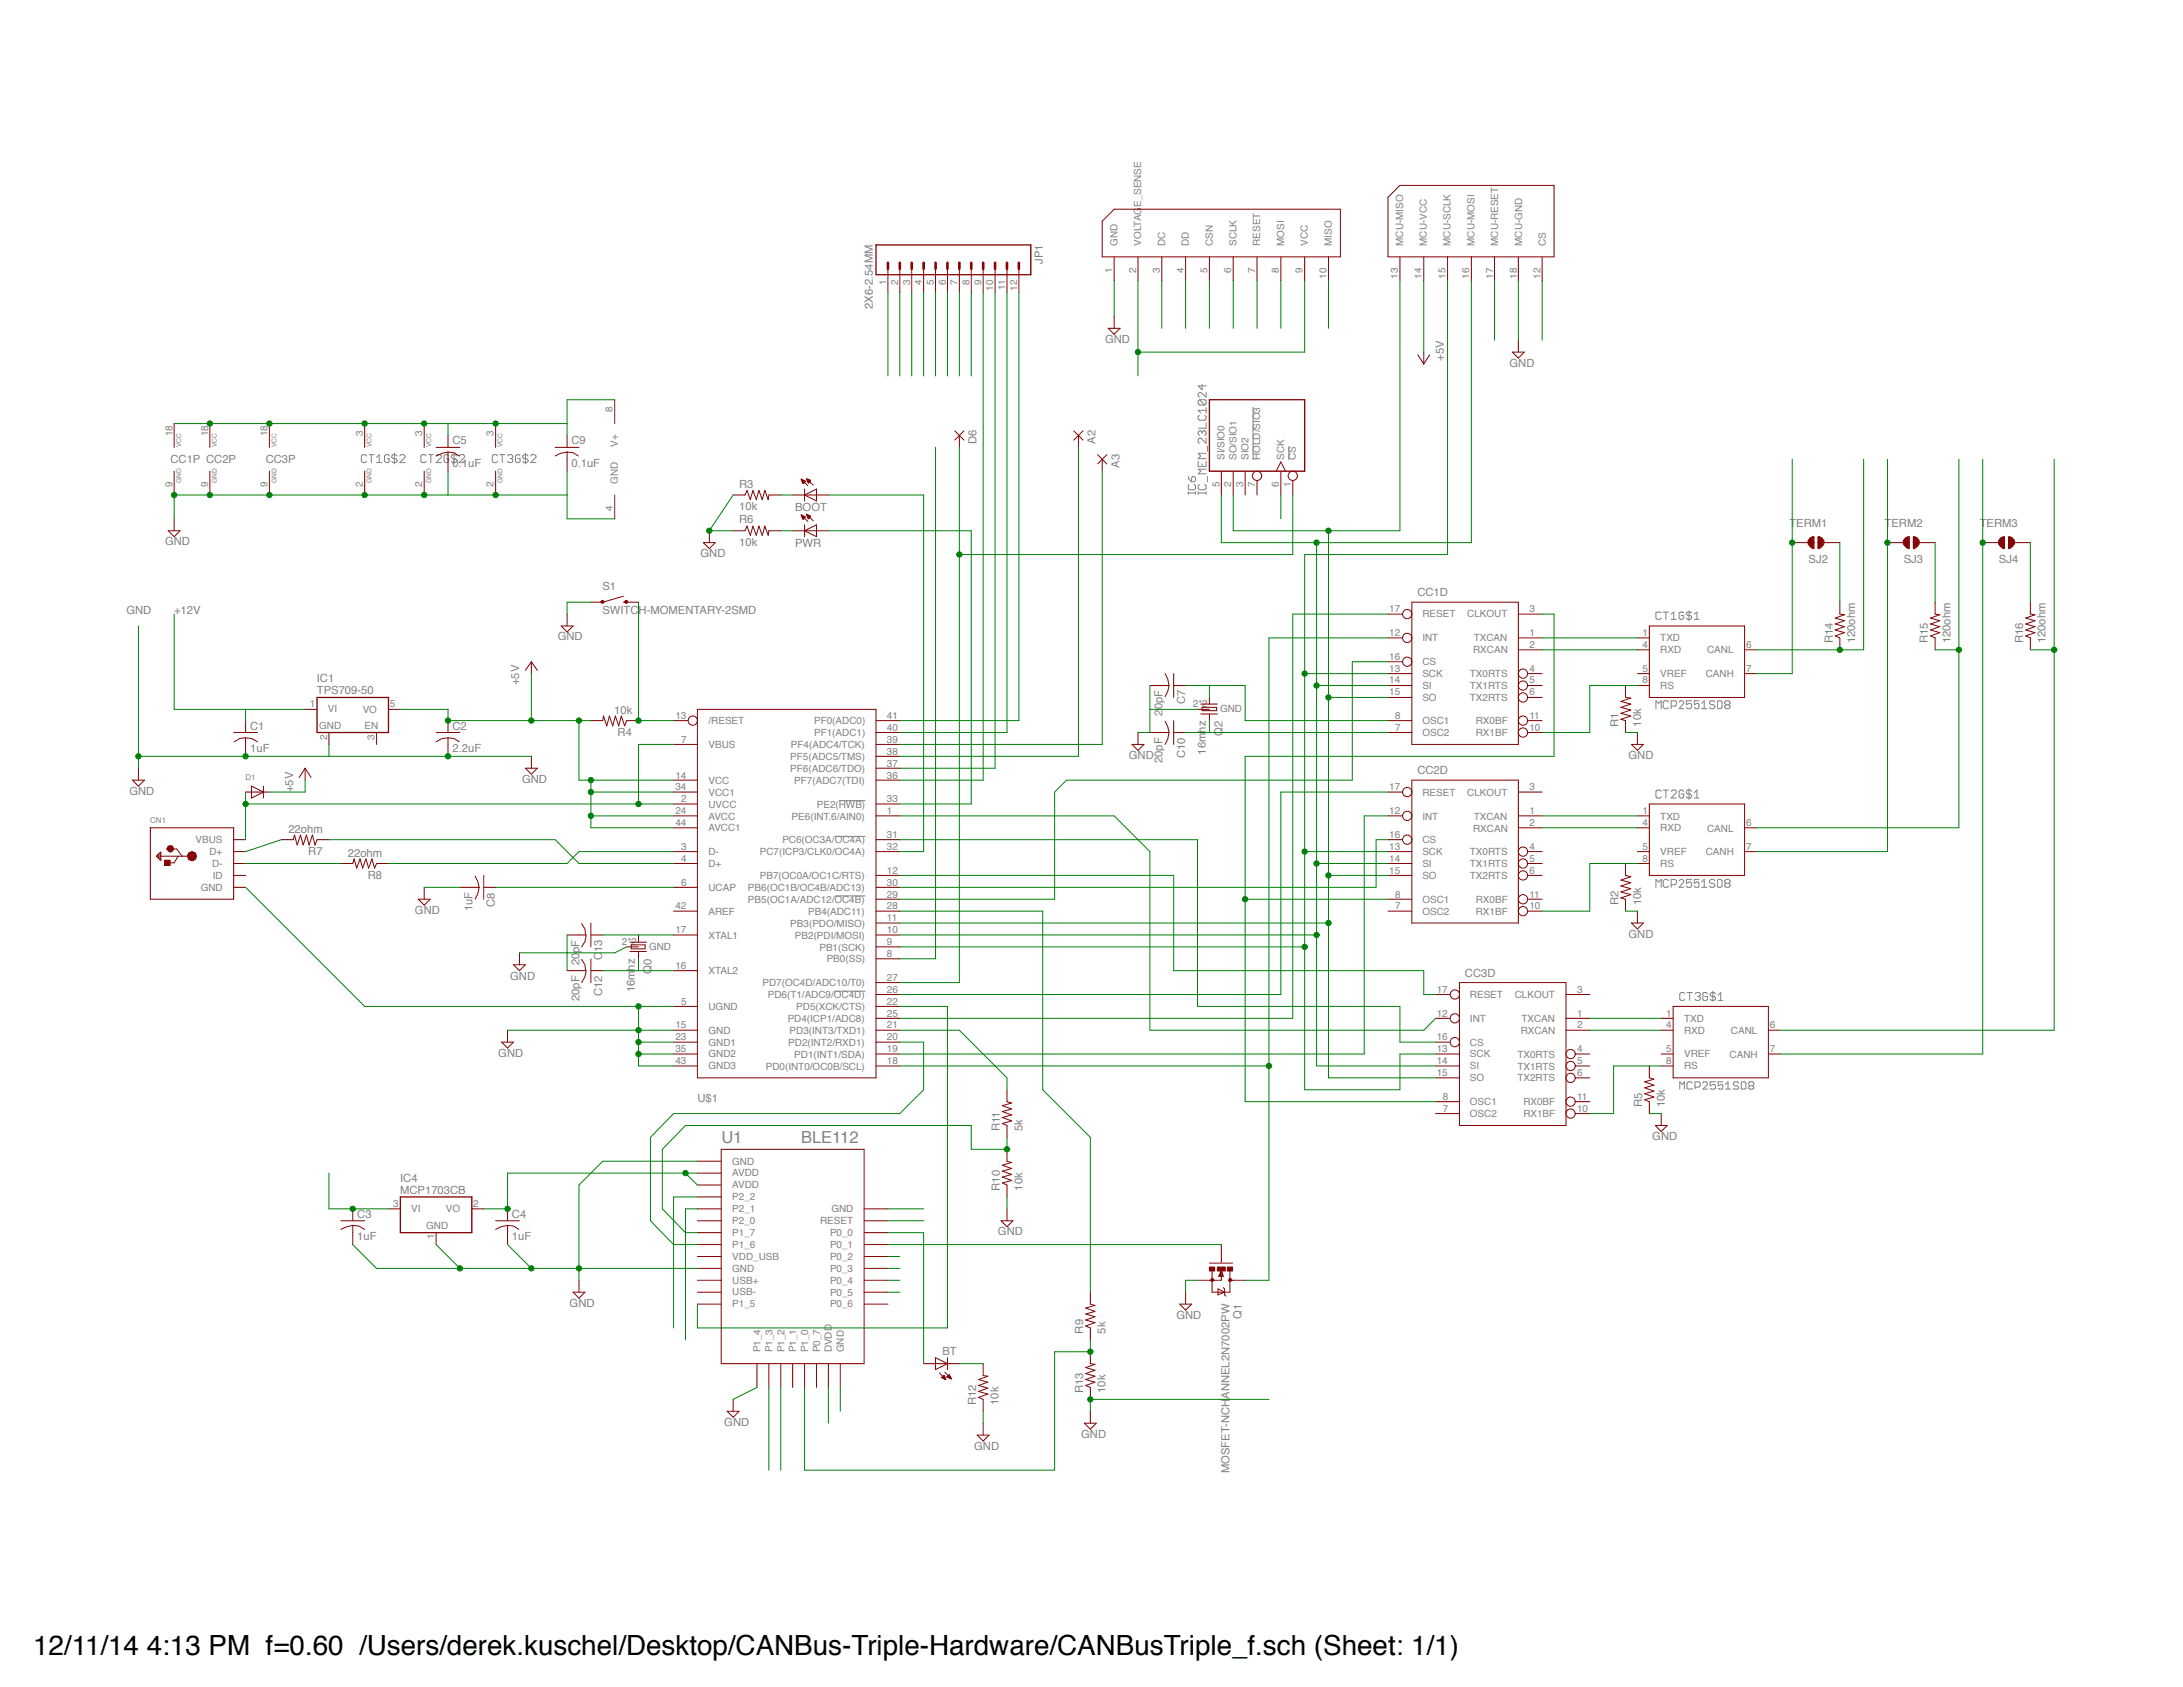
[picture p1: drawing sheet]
<svg xmlns="http://www.w3.org/2000/svg" width="279mm" height="216mm" viewBox="0 0 279 216" stroke-linecap="round" stroke-linejoin="round" font-family="sans-serif">
<defs><g id="words">
<text font-size="3.6" x="4.2" y="211.8">12/11/14 4:13 PM f=0.60 /Users/derek.kuschel/Desktop/CANBus-Triple-Hardware/CANBusTriple_f.sch (Sheet: 1/1)</text>
<g font-size="2.1" fill="#808080">
<text x="92.3" y="146.3">U1</text>
<text x="102.5" y="146.3">BLE112</text>
</g>
<g font-size="1.4" fill="#808080">
<text x="133.5" y="33.8" transform="rotate(-90 133.5 33.8)">JP1</text>
<text x="111.7" y="39.5" transform="rotate(-90 111.7 39.5)">2X6-2.54MM</text>
<text x="141.4" y="43.9">GND</text>
<text x="184.8" y="46.1" transform="rotate(-90 184.8 46.1)">+5V</text>
<text x="193.2" y="46.9">GND</text>
<text x="21.8" y="59.2">CC1P CC2P</text>
<text x="34" y="59.2">CC3P</text>
<text x="57.9" y="59.7">0.1uF</text>
<text x="57.9" y="56.8">C5</text>
<text x="73.1" y="59.7">0.1uF</text>
<text x="73.1" y="56.8">C9</text>
<text x="125" y="56.9" transform="rotate(-90 125 56.9)">D6</text>
<text x="140.2" y="56.8" transform="rotate(-90 140.2 56.8)">A2</text>
<text x="143.3" y="59.8" transform="rotate(-90 143.3 59.8)">A3</text>
<text x="94.6" y="65.3">10k</text>
<text x="94.6" y="62.4">R3</text>
<text x="101.8" y="65.4">BOOT</text>
<text x="21.1" y="69.8">GND</text>
<text x="89.7" y="71.3">GND</text>
<text x="94.6" y="69.9">10k</text>
<text x="94.6" y="67">R6</text>
<text x="101.8" y="70">PWR</text>
<text x="229" y="67.5">TERM1</text>
<text x="241.2" y="67.5">TERM2</text>
<text x="253.4" y="67.5">TERM3</text>
<text x="77.1" y="75.5">S1</text>
<text x="181.4" y="76.3">CC1D</text>
<text x="231.5" y="72">SJ2</text>
<text x="243.7" y="72">SJ3</text>
<text x="255.8" y="72">SJ4</text>
<text x="16.2" y="78.5">GND</text>
<text x="22.3" y="78.5">+12V</text>
<text x="71.4" y="82">GND</text>
<text x="77.1" y="78.5">SWITCH-MOMENTARY-2SMD</text>
<text x="234.6" y="82.3" transform="rotate(-90 234.6 82.3)">R14</text>
<text x="237.4" y="82.3" transform="rotate(-90 237.4 82.3)">120ohm</text>
<text x="246.7" y="82.3" transform="rotate(-90 246.7 82.3)">R15</text>
<text x="249.6" y="82.3" transform="rotate(-90 249.6 82.3)">120ohm</text>
<text x="258.9" y="82.3" transform="rotate(-90 258.9 82.3)">R16</text>
<text x="261.8" y="82.3" transform="rotate(-90 261.8 82.3)">120ohm</text>
<text x="40.6" y="88.8">TPS709-50</text>
<text x="40.6" y="87.3">IC1</text>
<text x="66.4" y="87.7" transform="rotate(-90 66.4 87.7)">+5V</text>
<text x="32" y="93.4">C1</text>
<text x="57.9" y="93.4">C2</text>
<text x="78.6" y="91.4">10k</text>
<text x="79" y="94.2">R4</text>
<text x="148.8" y="91.6" transform="rotate(-90 148.8 91.6)">20pF</text>
<text x="151.7" y="90.1" transform="rotate(-90 151.7 90.1)">C7</text>
<text x="156.5" y="94.2" transform="rotate(-90 156.5 94.2)">Q2</text>
<text x="207.2" y="93" transform="rotate(-90 207.2 93)">R1</text>
<text x="210" y="93" transform="rotate(-90 210 93)">10k</text>
<text x="16.6" y="101.8">GND</text>
<text x="32" y="96.3">1uF</text>
<text x="37.5" y="101.4" transform="rotate(-90 37.5 101.4)">+5V</text>
<text x="57.9" y="96.3">2.2uF</text>
<text x="66.8" y="100.2">GND</text>
<text x="144.5" y="97.2">GND</text>
<text x="148.8" y="97.7" transform="rotate(-90 148.8 97.7)">20pF</text>
<text x="151.7" y="97" transform="rotate(-90 151.7 97)">C10</text>
<text x="154.3" y="96.6" transform="rotate(-90 154.3 96.6)">16mhz</text>
<text x="181.4" y="99.1">CC2D</text>
<text x="208.4" y="97.2">GND</text>
<text x="36.9" y="106.6">22ohm</text>
<text x="39.4" y="109.5">R7</text>
<text x="44.5" y="109.6">22ohm</text>
<text x="47.1" y="112.5">R8</text>
<text x="53.1" y="117">GND</text>
<text x="60.5" y="116.6" transform="rotate(-90 60.5 116.6)">1uF</text>
<text x="63.4" y="116" transform="rotate(-90 63.4 116)">C8</text>
<text x="207.2" y="115.8" transform="rotate(-90 207.2 115.8)">R2</text>
<text x="210" y="115.8" transform="rotate(-90 210 115.8)">10k</text>
<text x="65.3" y="125.4">GND</text>
<text x="74.2" y="123.6" transform="rotate(-90 74.2 123.6)">20pF</text>
<text x="77.1" y="122.9" transform="rotate(-90 77.1 122.9)">C13</text>
<text x="83.4" y="124.6" transform="rotate(-90 83.4 124.6)">Q0</text>
<text x="187.5" y="125">CC3D</text>
<text x="208.4" y="120">GND</text>
<text x="74.2" y="128.1" transform="rotate(-90 74.2 128.1)">20pF</text>
<text x="77.1" y="127.5" transform="rotate(-90 77.1 127.5)">C12</text>
<text x="81.2" y="127" transform="rotate(-90 81.2 127)">16mhz</text>
<text x="63.8" y="135.3">GND</text>
<text x="89.3" y="141">U$1</text>
<text x="210.2" y="141.7" transform="rotate(-90 210.2 141.7)">R5</text>
<text x="213.1" y="141.7" transform="rotate(-90 213.1 141.7)">10k</text>
<text x="128" y="144.8" transform="rotate(-90 128 144.8)">R11</text>
<text x="130.8" y="144.8" transform="rotate(-90 130.8 144.8)">5k</text>
<text x="211.5" y="145.9">GND</text>
<text x="45.7" y="155.8">C3</text>
<text x="51.2" y="152.8">MCP1703CB</text>
<text x="51.2" y="151.2">IC4</text>
<text x="65.5" y="155.8">C4</text>
<text x="128" y="152.4" transform="rotate(-90 128 152.4)">R10</text>
<text x="130.8" y="152.4" transform="rotate(-90 130.8 152.4)">10k</text>
<text x="45.7" y="158.7">1uF</text>
<text x="65.5" y="158.7">1uF</text>
<text x="127.7" y="158.1">GND</text>
<text x="72.9" y="167.2">GND</text>
<text x="120.6" y="173.4">BT</text>
<text x="138.6" y="170.7" transform="rotate(-90 138.6 170.7)">R9</text>
<text x="141.5" y="170.7" transform="rotate(-90 141.5 170.7)">5k</text>
<text x="150.6" y="168.8">GND</text>
<text x="158.9" y="168.8" transform="rotate(-90 158.9 168.8)">Q1</text>
<text x="124.9" y="179.8" transform="rotate(-90 124.9 179.8)">R12</text>
<text x="127.8" y="179.8" transform="rotate(-90 127.8 179.8)">10k</text>
<text x="138.6" y="178.3" transform="rotate(-90 138.6 178.3)">R13</text>
<text x="141.5" y="178.3" transform="rotate(-90 141.5 178.3)">10k</text>
<text x="92.7" y="182.5">GND</text>
<text x="124.7" y="185.5">GND</text>
<text x="138.4" y="184">GND</text>
<text x="157.4" y="188.5" transform="rotate(-90 157.4 188.5)">MOSFET-NCHANNEL2N7002PW</text>
</g>
<g font-size="1.3" fill="#808080">
<text x="142.4" y="34.9" transform="rotate(-90 142.4 34.9)">1</text>
<text x="143" y="31.5" transform="rotate(-90 143 31.5)">GND</text>
<text x="145.4" y="34.9" transform="rotate(-90 145.4 34.9)">2</text>
<text x="146.1" y="31.5" transform="rotate(-90 146.1 31.5)">VOLTAGE_SENSE</text>
<text x="148.5" y="34.9" transform="rotate(-90 148.5 34.9)">3</text>
<text x="149.1" y="31.5" transform="rotate(-90 149.1 31.5)">DC</text>
<text x="151.5" y="34.9" transform="rotate(-90 151.5 34.9)">4</text>
<text x="152.2" y="31.5" transform="rotate(-90 152.2 31.5)">DD</text>
<text x="154.5" y="34.9" transform="rotate(-90 154.5 34.9)">5</text>
<text x="155.2" y="31.5" transform="rotate(-90 155.2 31.5)">CSN</text>
<text x="157.6" y="34.9" transform="rotate(-90 157.6 34.9)">6</text>
<text x="158.3" y="31.5" transform="rotate(-90 158.3 31.5)">SCLK</text>
<text x="160.6" y="34.9" transform="rotate(-90 160.6 34.9)">7</text>
<text x="161.3" y="31.5" transform="rotate(-90 161.3 31.5)">RESET</text>
<text x="163.7" y="34.9" transform="rotate(-90 163.7 34.9)">8</text>
<text x="164.3" y="31.5" transform="rotate(-90 164.3 31.5)">MOSI</text>
<text x="166.7" y="34.9" transform="rotate(-90 166.7 34.9)">9</text>
<text x="167.4" y="31.5" transform="rotate(-90 167.4 31.5)">VCC</text>
<text x="169.8" y="35.7" transform="rotate(-90 169.8 35.7)">10</text>
<text x="170.4" y="31.5" transform="rotate(-90 170.4 31.5)">MISO</text>
<text x="178.9" y="35.7" transform="rotate(-90 178.9 35.7)">13</text>
<text x="179.6" y="31.5" transform="rotate(-90 179.6 31.5)">MCU-MISO</text>
<text x="182" y="35.7" transform="rotate(-90 182 35.7)">14</text>
<text x="182.6" y="31.5" transform="rotate(-90 182.6 31.5)">MCU-VCC</text>
<text x="185" y="35.7" transform="rotate(-90 185 35.7)">15</text>
<text x="185.7" y="31.5" transform="rotate(-90 185.7 31.5)">MCU-SCLK</text>
<text x="188" y="35.7" transform="rotate(-90 188 35.7)">16</text>
<text x="188.7" y="31.5" transform="rotate(-90 188.7 31.5)">MCU-MOSI</text>
<text x="191.1" y="35.7" transform="rotate(-90 191.1 35.7)">17</text>
<text x="191.8" y="31.5" transform="rotate(-90 191.8 31.5)">MCU-RESET</text>
<text x="194.1" y="35.7" transform="rotate(-90 194.1 35.7)">18</text>
<text x="194.8" y="31.5" transform="rotate(-90 194.8 31.5)">MCU-GND</text>
<text x="197.2" y="35.7" transform="rotate(-90 197.2 35.7)">12</text>
<text x="197.9" y="31.5" transform="rotate(-90 197.9 31.5)">CS</text>
<text x="113.4" y="36.5" transform="rotate(-90 113.4 36.5)">1</text>
<text x="115" y="36.5" transform="rotate(-90 115 36.5)">2</text>
<text x="116.5" y="36.5" transform="rotate(-90 116.5 36.5)">3</text>
<text x="118" y="36.5" transform="rotate(-90 118 36.5)">4</text>
<text x="119.5" y="36.5" transform="rotate(-90 119.5 36.5)">5</text>
<text x="121" y="36.5" transform="rotate(-90 121 36.5)">6</text>
<text x="122.6" y="36.5" transform="rotate(-90 122.6 36.5)">7</text>
<text x="124.1" y="36.5" transform="rotate(-90 124.1 36.5)">8</text>
<text x="125.6" y="36.5" transform="rotate(-90 125.6 36.5)">9</text>
<text x="127.1" y="37.2" transform="rotate(-90 127.1 37.2)">10</text>
<text x="128.7" y="37.1" transform="rotate(-90 128.7 37.1)">11</text>
<text x="130.2" y="37.2" transform="rotate(-90 130.2 37.2)">12</text>
<text x="78.4" y="52.8" transform="rotate(-90 78.4 52.8)">8</text>
<text x="22.1" y="55.8" transform="rotate(-90 22.1 55.8)">18</text>
<text x="26.6" y="55.8" transform="rotate(-90 26.6 55.8)">18</text>
<text x="34.2" y="55.8" transform="rotate(-90 34.2 55.8)">18</text>
<text x="46.4" y="55.8" transform="rotate(-90 46.4 55.8)">3</text>
<text x="54" y="55.8" transform="rotate(-90 54 55.8)">3</text>
<text x="63.2" y="55.8" transform="rotate(-90 63.2 55.8)">3</text>
<text x="79.1" y="57.2" transform="rotate(-90 79.1 57.2)">V+</text>
<text x="156.7" y="58.9" transform="rotate(-90 156.7 58.9)">SI/SIO0</text>
<text x="158.3" y="58.9" transform="rotate(-90 158.3 58.9)">SO/SIO1</text>
<text x="159.8" y="58.9" transform="rotate(-90 159.8 58.9)">SIO2</text>
<text x="161.3" y="58.9" transform="rotate(-90 161.3 58.9)">HOLD/SIO3</text>
<text x="164.3" y="58.9" transform="rotate(-90 164.3 58.9)">SCK</text>
<text x="165.9" y="58.9" transform="rotate(-90 165.9 58.9)">CS</text>
<text x="22.1" y="62.3" transform="rotate(-90 22.1 62.3)">9</text>
<text x="26.6" y="62.3" transform="rotate(-90 26.6 62.3)">9</text>
<text x="34.2" y="62.3" transform="rotate(-90 34.2 62.3)">9</text>
<text x="46.4" y="62.3" transform="rotate(-90 46.4 62.3)">2</text>
<text x="54" y="62.3" transform="rotate(-90 54 62.3)">2</text>
<text x="63.2" y="62.3" transform="rotate(-90 63.2 62.3)">2</text>
<text x="78.4" y="65.4" transform="rotate(-90 78.4 65.4)">4</text>
<text x="79.1" y="61.9" transform="rotate(-90 79.1 61.9)">GND</text>
<text x="156.1" y="62.3" transform="rotate(-90 156.1 62.3)">5</text>
<text x="157.6" y="62.3" transform="rotate(-90 157.6 62.3)">2</text>
<text x="159.1" y="62.3" transform="rotate(-90 159.1 62.3)">3</text>
<text x="160.6" y="62.3" transform="rotate(-90 160.6 62.3)">7</text>
<text x="163.7" y="62.3" transform="rotate(-90 163.7 62.3)">6</text>
<text x="165.2" y="62.3" transform="rotate(-90 165.2 62.3)">1</text>
<text x="177.8" y="81.4">12</text>
<text x="177.8" y="78.3">17</text>
<text x="182" y="82">INT</text>
<text x="182" y="79">RESET</text>
<text x="187.8" y="79">CLKOUT</text>
<text x="188.5" y="83.6">RXCAN</text>
<text x="188.6" y="82.1">TXCAN</text>
<text x="195.7" y="78.3">3</text>
<text x="195.7" y="82.9">2</text>
<text x="195.7" y="81.4">1</text>
<text x="210.2" y="82.9">4</text>
<text x="210.2" y="81.4">1</text>
<text x="212.5" y="83.6">RXD</text>
<text x="212.5" y="82">TXD</text>
<text x="218.5" y="83.6">CANL</text>
<text x="223.5" y="82.9">6</text>
<text x="177.8" y="84.4">16</text>
<text x="177.8" y="85.9">13</text>
<text x="177.8" y="87.5">14</text>
<text x="177.8" y="89">15</text>
<text x="182" y="85.1">CS</text>
<text x="182" y="86.6">SCK</text>
<text x="182" y="88.1">SI</text>
<text x="182" y="89.7">SO</text>
<text x="188.1" y="86.6">TX0RTS</text>
<text x="188.1" y="88.1">TX1RTS</text>
<text x="188.1" y="89.7">TX2RTS</text>
<text x="195.7" y="85.9">4</text>
<text x="195.7" y="87.5">5</text>
<text x="195.7" y="89">6</text>
<text x="210.2" y="87.5">8</text>
<text x="210.2" y="85.9">5</text>
<text x="212.5" y="88.1">RS</text>
<text x="212.5" y="86.6">VREF</text>
<text x="218.3" y="86.6">CANH</text>
<text x="223.5" y="85.9">7</text>
<text x="39.7" y="90.5">1</text>
<text x="40.9" y="93.3">GND</text>
<text x="41.9" y="94.7" transform="rotate(-90 41.9 94.7)">2</text>
<text x="42" y="91.2">VI</text>
<text x="46.4" y="91.2">VO</text>
<text x="46.6" y="93.3">EN</text>
<text x="48" y="94.7" transform="rotate(-90 48 94.7)">3</text>
<text x="49.9" y="90.5">5</text>
<text x="86.4" y="92">13</text>
<text x="87.2" y="95.1">7</text>
<text x="90.7" y="92.7">/RESET</text>
<text x="90.7" y="95.7">VBUS</text>
<text x="101.2" y="95.8">PF4(ADC4/TCK)</text>
<text x="104.2" y="92.7">PF0(ADC0)</text>
<text x="104.2" y="94.2">PF1(ADC1)</text>
<text x="113.5" y="92">41</text>
<text x="113.5" y="93.6">40</text>
<text x="113.5" y="95.1">39</text>
<text x="152.7" y="90.5">2*2</text>
<text x="156.2" y="91.2">GND</text>
<text x="178.6" y="92">8</text>
<text x="178.6" y="93.6">7</text>
<text x="182" y="92.7">OSC1</text>
<text x="182" y="94.2">OSC2</text>
<text x="188.9" y="92.7">RX0BF</text>
<text x="188.9" y="94.2">RX1BF</text>
<text x="195.7" y="92">11</text>
<text x="195.7" y="93.6">10</text>
<text x="86.4" y="99.6">14</text>
<text x="86.4" y="101.2">34</text>
<text x="90.7" y="100.3">VCC</text>
<text x="90.7" y="101.8">VCC1</text>
<text x="101.2" y="97.3">PF5(ADC5/TMS)</text>
<text x="101.2" y="98.8">PF6(ADC6/TDO)</text>
<text x="101.7" y="100.3">PF7(ADC7(TDI)</text>
<text x="113.5" y="96.6">38</text>
<text x="113.5" y="98.1">37</text>
<text x="113.5" y="99.6">36</text>
<text x="177.8" y="101.2">17</text>
<text x="182" y="101.8">RESET</text>
<text x="187.8" y="101.9">CLKOUT</text>
<text x="195.7" y="101.2">3</text>
<text x="25" y="107.9">VBUS</text>
<text x="86.4" y="104.2">24</text>
<text x="86.4" y="105.7">44</text>
<text x="87.2" y="102.7">2</text>
<text x="90.7" y="103.4">UVCC</text>
<text x="90.7" y="104.9">AVCC</text>
<text x="90.7" y="106.4">AVCC1</text>
<text x="100.1" y="107.9">PC6(OC3A/OC4A)</text>
<text x="101.3" y="104.9">PE6(INT.6/AIN0)</text>
<text x="104.5" y="103.4">PE2(HWB)</text>
<text x="113.5" y="107.3">31</text>
<text x="113.5" y="102.7">33</text>
<text x="113.5" y="104.2">1</text>
<text x="177.8" y="107.3">16</text>
<text x="177.8" y="104.2">12</text>
<text x="182" y="107.9">CS</text>
<text x="182" y="104.9">INT</text>
<text x="188.5" y="106.4">RXCAN</text>
<text x="188.6" y="104.9">TXCAN</text>
<text x="195.7" y="105.7">2</text>
<text x="195.7" y="104.2">1</text>
<text x="210.2" y="105.7">4</text>
<text x="210.2" y="104.2">1</text>
<text x="212.5" y="106.4">RXD</text>
<text x="212.5" y="104.9">TXD</text>
<text x="218.5" y="106.4">CANL</text>
<text x="223.5" y="105.7">6</text>
<text x="26.8" y="109.5">D+</text>
<text x="27.1" y="111">D-</text>
<text x="27.2" y="112.5">ID</text>
<text x="87.2" y="108.8">3</text>
<text x="87.2" y="110.3">4</text>
<text x="87.2" y="113.3">6</text>
<text x="90.7" y="109.4">D-</text>
<text x="90.7" y="111">D+</text>
<text x="97.3" y="109.5">PC7(ICP3/CLK0/OC4A)</text>
<text x="97.3" y="112.5">PB7(OC0A/OC1C/RTS)</text>
<text x="113.5" y="108.8">32</text>
<text x="113.5" y="113.3">30</text>
<text x="113.5" y="111.8">12</text>
<text x="177.8" y="108.8">13</text>
<text x="177.8" y="110.3">14</text>
<text x="177.8" y="111.8">15</text>
<text x="182" y="109.4">SCK</text>
<text x="182" y="111">SI</text>
<text x="182" y="112.5">SO</text>
<text x="188.1" y="109.5">TX0RTS</text>
<text x="188.1" y="111">TX1RTS</text>
<text x="188.1" y="112.5">TX2RTS</text>
<text x="195.7" y="108.8">4</text>
<text x="195.7" y="110.3">5</text>
<text x="195.7" y="111.8">6</text>
<text x="210.2" y="110.3">8</text>
<text x="210.2" y="108.8">5</text>
<text x="212.5" y="111">RS</text>
<text x="212.5" y="109.4">VREF</text>
<text x="218.3" y="109.5">CANH</text>
<text x="223.5" y="108.8">7</text>
<text x="25.7" y="114">GND</text>
<text x="86.4" y="119.4">17</text>
<text x="86.4" y="116.4">42</text>
<text x="90.7" y="114">UCAP</text>
<text x="90.7" y="117.1">AREF</text>
<text x="95.7" y="114">PB6(OC1B/OC4B/ADC13)</text>
<text x="95.7" y="115.6">PB5(OC1A/ADC12/OC4B)</text>
<text x="101.2" y="118.6">PB3(PDO/MISO)</text>
<text x="103.4" y="117.1">PB4(ADC11)</text>
<text x="113.5" y="117.9">11</text>
<text x="113.5" y="119.4">10</text>
<text x="113.5" y="116.4">28</text>
<text x="113.5" y="114.9">29</text>
<text x="178.6" y="114.9">8</text>
<text x="178.6" y="116.4">7</text>
<text x="182" y="115.5">OSC1</text>
<text x="182" y="117.1">OSC2</text>
<text x="188.9" y="115.6">RX0BF</text>
<text x="188.9" y="117.1">RX1BF</text>
<text x="195.7" y="114.9">11</text>
<text x="195.7" y="116.4">10</text>
<text x="79.6" y="121">2*2</text>
<text x="83.1" y="121.6">GND</text>
<text x="86.4" y="124">16</text>
<text x="90.7" y="124.7">XTAL2</text>
<text x="90.7" y="120.1">XTAL1</text>
<text x="101.7" y="120.1">PB2(PDI/MOSI)</text>
<text x="104.9" y="121.6">PB1(SCK)</text>
<text x="105.8" y="123.2">PB0(SS)</text>
<text x="113.5" y="121">9</text>
<text x="113.5" y="122.5">8</text>
<text x="113.5" y="125.5">27</text>
<text x="86.4" y="131.6">15</text>
<text x="87.2" y="128.6">5</text>
<text x="90.7" y="129.2">UGND</text>
<text x="97.6" y="126.2">PD7(OC4D/ADC10/T0)</text>
<text x="98.3" y="127.7">PD6(T1/ADC9/OC4D)</text>
<text x="100.8" y="130.8">PD4(ICP1/ADC8)</text>
<text x="101.9" y="129.3">PD5(XCK/CTS)</text>
<text x="113.5" y="127.1">26</text>
<text x="113.5" y="128.6">22</text>
<text x="113.5" y="130.1">25</text>
<text x="113.5" y="131.6">21</text>
<text x="183.9" y="130.1">12</text>
<text x="183.9" y="127.1">17</text>
<text x="188.1" y="130.8">INT</text>
<text x="188.1" y="127.7">RESET</text>
<text x="193.9" y="127.7">CLKOUT</text>
<text x="194.7" y="130.8">TXCAN</text>
<text x="201.8" y="127.1">3</text>
<text x="201.8" y="131.6">2</text>
<text x="201.8" y="130.1">1</text>
<text x="213.3" y="131.6">4</text>
<text x="213.3" y="130.1">1</text>
<text x="215.5" y="130.8">TXD</text>
<text x="226.5" y="131.6">6</text>
<text x="86.4" y="133.1">23</text>
<text x="86.4" y="134.7">35</text>
<text x="86.4" y="136.2">43</text>
<text x="90.7" y="132.3">GND</text>
<text x="90.7" y="133.8">GND1</text>
<text x="90.7" y="135.3">GND2</text>
<text x="90.7" y="136.9">GND3</text>
<text x="98" y="136.9">PD0(INT0/OC0B/SCL)</text>
<text x="100.9" y="133.8">PD2(INT2/RXD1)</text>
<text x="101.1" y="132.3">PD3(INT3/TXD1)</text>
<text x="101.7" y="135.4">PD1(INT1/SDA)</text>
<text x="113.5" y="133.1">20</text>
<text x="113.5" y="134.7">19</text>
<text x="113.5" y="136.2">18</text>
<text x="183.9" y="133.1">16</text>
<text x="183.9" y="134.7">13</text>
<text x="183.9" y="136.2">14</text>
<text x="183.9" y="137.7">15</text>
<text x="188.1" y="133.8">CS</text>
<text x="188.1" y="135.3">SCK</text>
<text x="188.1" y="136.9">SI</text>
<text x="194.2" y="135.4">TX0RTS</text>
<text x="194.2" y="136.9">TX1RTS</text>
<text x="194.6" y="132.3">RXCAN</text>
<text x="201.8" y="134.7">4</text>
<text x="201.8" y="136.2">5</text>
<text x="201.8" y="137.7">6</text>
<text x="213.3" y="136.2">8</text>
<text x="213.3" y="134.7">5</text>
<text x="215.5" y="136.9">RS</text>
<text x="215.5" y="132.3">RXD</text>
<text x="215.5" y="135.3">VREF</text>
<text x="221.4" y="135.4">CANH</text>
<text x="221.5" y="132.3">CANL</text>
<text x="226.5" y="134.7">7</text>
<text x="184.7" y="140.8">8</text>
<text x="184.7" y="142.3">7</text>
<text x="188.1" y="141.4">OSC1</text>
<text x="188.1" y="142.9">OSC2</text>
<text x="188.1" y="138.4">SO</text>
<text x="194.2" y="138.4">TX2RTS</text>
<text x="195" y="141.4">RX0BF</text>
<text x="195" y="143">RX1BF</text>
<text x="201.8" y="140.8">11</text>
<text x="201.8" y="142.3">10</text>
<text x="93.7" y="149">GND</text>
<text x="50.3" y="154.5">3</text>
<text x="52.6" y="155.1">VI</text>
<text x="57.1" y="155.1">VO</text>
<text x="60.6" y="154.5">2</text>
<text x="93.7" y="150.6">AVDD</text>
<text x="93.7" y="152.1">AVDD</text>
<text x="93.7" y="155.1">P2_1</text>
<text x="93.7" y="153.6">P2_2</text>
<text x="106.4" y="155.1">GND</text>
<text x="54.6" y="157.3">GND</text>
<text x="55.6" y="158.6" transform="rotate(-90 55.6 158.6)">1</text>
<text x="93.7" y="159.7">P1_6</text>
<text x="93.7" y="158.2">P1_7</text>
<text x="93.7" y="156.7">P2_0</text>
<text x="93.7" y="161.2">VDD_USB</text>
<text x="105" y="156.7">RESET</text>
<text x="106.2" y="158.2">P0_0</text>
<text x="106.2" y="159.7">P0_1</text>
<text x="106.2" y="161.2">P0_2</text>
<text x="93.7" y="162.7">GND</text>
<text x="93.7" y="167.3">P1_5</text>
<text x="93.7" y="164.3">USB+</text>
<text x="93.7" y="165.8">USB-</text>
<text x="106.2" y="162.8">P0_3</text>
<text x="106.2" y="164.3">P0_4</text>
<text x="106.2" y="165.8">P0_5</text>
<text x="106.2" y="167.3">P0_6</text>
<text x="97.3" y="173.1" transform="rotate(-90 97.3 173.1)">P1_4</text>
<text x="98.9" y="173.1" transform="rotate(-90 98.9 173.1)">P1_3</text>
<text x="100.4" y="173.1" transform="rotate(-90 100.4 173.1)">P1_2</text>
<text x="101.9" y="173.1" transform="rotate(-90 101.9 173.1)">P1_1</text>
<text x="103.4" y="173.1" transform="rotate(-90 103.4 173.1)">P1_0</text>
<text x="105" y="173.1" transform="rotate(-90 105 173.1)">P0_7</text>
<text x="106.5" y="173.1" transform="rotate(-90 106.5 173.1)">DVDD</text>
<text x="108" y="173.1" transform="rotate(-90 108 173.1)">GND</text>
</g>
<g font-size="1" fill="#808080">
<text x="31.4" y="99.9">D1</text>
<text x="19.2" y="105.3">CN1</text>
</g>
<g font-size=".8" fill="#808080">
<text x="23.2" y="57.2" transform="rotate(-90 23.2 57.2)">VCC</text>
<text x="27.8" y="57.2" transform="rotate(-90 27.8 57.2)">VCC</text>
<text x="35.4" y="57.2" transform="rotate(-90 35.4 57.2)">VCC</text>
<text x="47.6" y="57.2" transform="rotate(-90 47.6 57.2)">VCC</text>
<text x="55.2" y="57.2" transform="rotate(-90 55.2 57.2)">VCC</text>
<text x="64.3" y="57.2" transform="rotate(-90 64.3 57.2)">VCC</text>
<text x="23.2" y="61.8" transform="rotate(-90 23.2 61.8)">GND</text>
<text x="27.8" y="61.8" transform="rotate(-90 27.8 61.8)">GND</text>
<text x="35.4" y="61.8" transform="rotate(-90 35.4 61.8)">GND</text>
<text x="47.6" y="61.8" transform="rotate(-90 47.6 61.8)">GND</text>
<text x="55.2" y="61.8" transform="rotate(-90 55.2 61.8)">GND</text>
<text x="64.3" y="61.8" transform="rotate(-90 64.3 61.8)">GND</text>
</g>
</g></defs>
<g fill="none" stroke="#808080" stroke-width=".13">
<path d="M46.9 58.4l-.1-.2h-.4l-.2 .2v.6l.2 .2h.4l.1-.2M47.3 58.2h.6M47.5 58.2v1M48.2 59.2h.7M48.2 58.5l.3-.3v1M49.8 58.4l-.1-.2h-.3l-.2 .2v.6l.2 .2h.3l.1-.2v-.3h-.2M50.5 58v1.4M50.8 58.4l-.1-.2h-.4l-.2 .2v.1l.2 .2h.4l.1 .2v.1l-.1 .2h-.4l-.2-.2M51.2 58.4l.1-.2h.4l.1 .2v.1l-.6 .7h.6M54.5 58.4l-.1-.2h-.4l-.1 .2v.6l.1 .2h.4l.1-.2M54.9 58.2h.6M55.1 58.2v1"/>
<path d="M55.8 58.4l.2-.2h.3l.2 .2v.1l-.7 .7h.7M57.4 58.4l-.1-.2h-.3l-.2 .2v.6l.2 .2h.3l.1-.2v-.3h-.2M58.1 58v1.4M58.4 58.4l-.1-.2h-.4l-.1 .2v.1l.1 .2h.4l.1 .2v.1l-.1 .2h-.4l-.1-.2M58.8 58.4l.1-.2h.4l.2 .2v.1l-.7 .7h.7M63.7 58.4l-.2-.2h-.3l-.2 .2v.6l.2 .2h.3l.2-.2M63.9 58.2h.7M64.3 58.2v1M65 58.4l.1-.2h.4l.1 .2v.1l-.1 .2M65.3 58.7h.2M65.5 58.7l.1 .2v.1l-.1 .2h-.4l-.1-.2M66.6 58.4l-.2-.2h-.3l-.1 .2v.6l.1 .2h.3l.2-.2v-.3h-.4"/>
<path d="M67.2 58v1.4M67.6 58.4l-.2-.2h-.3l-.2 .2v.1l.2 .2h.3l.2 .2v.1l-.2 .2h-.3l-.2-.2M67.9 58.4l.2-.2h.3l.2 .2v.1l-.7 .7h.7M153.4 59v.7h1v-.7M153.5 51.2h.7l.2 .1v.4l-.2 .1M153.5 53.2l-.1 .1v.3l.1 .2h.7l.2-.2v-.3l-.2-.1M153.5 51.2l-.1 .1v.4l.1 .1h.7M153.5 51.2l.7 .6M153.9 55.3l.1-.2h.2l.2 .2v.3l-.2 .1M153.9 55.3l-.2-.2h-.2l-.1 .2v.3l.1 .1M153.9 49.2v.7l-.5-.5h1M153.9 55.3v.2"/>
<path d="M153.9 59.4v.3M154.4 50.2v.6l-.7-.6h-.2l-.1 .2v.3l.1 .1M154.4 52.2v.7M154.4 54.1v.7h-1M154.4 56.1v.6l-.7-.6h-.2l-.1 .1v.4l.1 .1M154.4 58h-1l.3 .4-.3 .3h1M154.4 52.5h-1l.3 .4M154.5 57.1v.7M160.4 52.1v6.8M165 57.1v1.8M152.1 63.1h.9M152.1 61l.1 .3 .3 .4"/>
<path d="M152.1 62.9v.4M152.2 62l-.1 .2 .1 .5h.6l.2-.2v-.3l-.2-.2M152.5 61.2l.2-.2h.1l.2 .2v.3l-.2 .2h-.3zM153 62.9v.4M153.4 63.1h1M153.4 62.9v.4M153.5 62l-.1 .2v.3l.1 .2h.7l.2-.2v-.3l-.2-.2M154.4 62.9v.4M154.4 60h-1l.3 .3-.3 .3h1M154.5 61v.7M212.6 78.4l-.2-.1-.5 .1v.7l.2 .2h.3l.2-.2M212.9 78.3h.7"/>
<path d="M213.2 78.3v1M213.9 79.3h.7M213.9 78.6l.3-.3v1M215.5 78.4l-.2-.1-.4 .1v.7l.2 .2h.2l.2-.2v-.3h-.3M216.2 78.2v1.2M216.5 78.4l-.2-.1-.5 .1v.2l.2 .2h.3l.2 .1v.2l-.2 .2h-.3l-.2-.2M216.9 79.3h.5M216.9 78.6l.3-.3v1M211.9 90.7v-1l.4 .3 .3-.3v1M213.6 89.9l-.2-.2h-.4l-.1 .2v.6l.1 .2h.4l.2-.2M213.9 90.4h.5l.2-.2v-.3l-.2-.2h-.5v1M214.9 89.9l.2-.2h.2l.2 .2v.1l-.6 .7h.6"/>
<path d="M216.5 89.7h-.7v.5l.4-.2h.1l.2 .2v.3l-.2 .2h-.3l-.2-.2M217.4 89.7h-.5v.5l.5-.2v.2v.5h-.4l-.1-.2M217.8 90.7h.7M217.8 90l.3-.3v1M219.5 89.9l-.2-.2h-.3l-.2 .2v.1l.2 .2h.3l.2 .2v.1l-.2 .2h-.3l-.2-.2M219.9 89.7h.3l.2 .2v.6l-.2 .2h-.3l-.1-.2v-.6zM220.9 90.2l-.2-.2v-.1l.2-.2h.4l.1 .2v.1l-.1 .2M220.9 90.2l-.2 .2v.1l.2 .2h.4l.1-.2v-.1l-.1-.2M220.9 90.2h.4M106.9 107h3.9M106.9 114.7h3.9M107.4 102.5h3.4"/>
<path d="M211.9 113.6v-1.1l.4 .4 .3-.4v1.1M212.6 101.3l-.2-.2h-.3l-.2 .2v.7l.2 .1h.3l.2-.1M212.9 101.1h.7M213.2 101.1v1M213.6 112.7l-.2-.2h-.4l-.1 .2v.7l.1 .2h.4l.2-.2M213.9 113.2h.5l.2-.1v-.4l-.2-.2h-.5v1.1M213.9 101.3l.2-.2h.3l.2 .2v.2l-.7 .6h.7M214.9 112.7l.2-.2h.2l.2 .2v.2l-.6 .7h.6M215.5 101.3l-.2-.2h-.2l-.2 .2v.7l.2 .1h.2l.2-.1v-.4h-.3M216.2 100.9v1.4M216.5 101.3l-.2-.2h-.3l-.2 .2v.2l.2 .1h.3l.2 .2v.2l-.2 .1h-.3l-.2-.1M216.5 112.5h-.7v.6l.4-.2h.1l.2 .2v.3l-.2 .2h-.3l-.2-.2"/>
<path d="M216.9 101.5l.3-.4v1M216.9 102.1h.5M217.4 112.5h-.5v.6l.5-.2v.2v.5h-.4l-.1-.2M217.8 112.9l.3-.4v1.1M217.8 113.6h.7M219.5 112.7l-.2-.2h-.3l-.2 .2v.2l.2 .2h.3l.2 .1v.2l-.2 .2h-.3l-.2-.2M219.9 112.5h.3l.2 .2v.7l-.2 .2h-.3l-.1-.2v-.7zM220.9 113.1l-.2-.2v-.2l.2-.2h.4l.1 .2v.2l-.1 .2M220.9 113.1l-.2 .1v.2l.2 .2h.4l.1-.2v-.2l-.1-.1M220.9 113.1h.4M106.8 126.9h4M215 139.4v-.9l.3 .3 .3-.3v.9"/>
<path d="M215.6 127.2l-.1-.2h-.3l-.2 .2v.7l.2 .1h.3l.1-.1M215.9 127h.7M216.3 127v1M216.6 138.6l-.2-.1h-.3l-.2 .1v.7l.2 .1 .5-.1M216.9 127.2l.2-.2h.3l.2 .2v.2l-.2 .1M216.9 139.1h.5l.2-.1v-.4l-.2-.1h-.5v.9M217.3 127.5h.1M217.4 127.5l.2 .2v.2l-.2 .1h-.3l-.2-.1M218 138.6v-.1h.4l.1 .1v.2l-.5 .6h.5M218.5 127.2l-.1-.2h-.4v.2v.7v.1h.4l.1-.1v-.4h-.3M219.2 126.9v1.2M219.6 127.2l-.2-.2h-.3l-.2 .2v.2l.2 .1h.3l.2 .2v.2l-.2 .1h-.3l-.2-.1"/>
<path d="M219.6 138.5h-.7v.5l.3-.2h.2l.2 .2v.3l-.2 .1-.5-.1M219.9 128h.6M219.9 127.4l.3-.4v1M220.5 138.5h-.6v.5l.3-.2h.2l.1 .2v.3l-.1 .1-.5-.1M220.8 139.4h.7M220.8 138.8l.4-.3v.9M222.5 138.6l-.1-.1h-.4l-.2 .1v.2l.2 .2h.4l.1 .1v.2l-.1 .1-.6-.1M222.9 138.5h.4l.2 .1v.7l-.2 .1h-.4v-.1v-.7zM224 139l-.2-.2v-.2l.2-.1h.3l.2 .1v.2l-.2 .2M224 139l-.2 .1v.2l.2 .1 .5-.1v-.2l-.2-.1M224 139h.3"/>
</g>
<g fill="none" stroke="#830203" stroke-width=".13">
<path d="M22.3 54.2v3.1M26.9 54.2v3.1M46.7 54.2v3.1M54.3 54.2v3.1M22.3 60.3v3.1M26.9 60.3v3.1M46.7 60.3v3.1M54.3 60.3v3.1M177.7 78.6h1.8M180.7 77.1h13.6v18.2h-13.6zM194.3 78.6h3.1M29.9 93.7h3.1"/>
<path d="M31.4 94.4l.8 .1 .8 .4M31.4 94.4l-.7 .1-.7 .4M31.4 92.2v1.5M31.4 94.4v2.4M55.8 93.7h3.1M57.3 94.4l.8 .1 .7 .4M57.3 94.4l-.7 .1-.8 .4M57.3 92.2v1.5M57.3 94.4v2.4M86.2 99.8h3.1M86.2 92.2h1.9M86.2 95.3h3.1"/>
<path d="M89.3 90.8h22.8v47.1h-22.8zM112.1 93.7h3.1M112.1 99.8h3.1M112.1 92.2h3.1M112.1 95.3h3.1M112.1 96.8h3.1M112.1 98.3h3.1M177.7 93.7h3M177.7 92.2h3M177.7 84.7h1.8M177.7 81.6h1.8M177.7 86.2h3"/>
<path d="M177.7 87.7h3M177.7 89.3h3M180.7 99.8h13.6v18.3h-13.6zM194.3 81.6h3.1M194.3 83.2h3.1M195.5 93.7h1.9M195.5 92.2h1.9M195.5 86.2h1.9M195.5 87.7h1.9M195.5 89.3h1.9M209.6 81.6h1.5M209.6 83.2h1.5"/>
<path d="M209.6 86.2h1.5M209.6 87.7h1.5M211.1 80.1h12.2v9.2h-12.2zM223.3 83.2h1.5M223.3 86.2h1.5M19.2 105.9h10.7v9.2h-10.7zM20.1 109.6l.2-.3v.5v-.2M20.5 109.1h.1v1l-.6-.5zM20.5 109.1v.8M20.6 109.6h4M22 108.6h.6l.7 1M22.8 109.6l-.5 .8h-.7"/>
<path d="M86.2 119.7h3.1M86.2 102.9h3.1M86.2 109h3.1M86.2 104.4h3.1M86.2 116.6h3.1M86.2 113.6h3.1M86.2 110.5h3.1M86.2 105.9h3.1M86.2 101.4h3.1M112.1 119.7h3.1M112.1 102.9h3.1M112.1 109h3.1"/>
<path d="M112.1 104.4h3.1M112.1 118.1h3.1M112.1 107.5h3.1M112.1 116.6h3.1M112.1 113.6h3.1M112.1 115.1h3.1M112.1 112h3.1M177.7 109h3M177.7 104.4h1.8M177.7 107.5h1.8M177.7 116.6h3M177.7 115.1h3"/>
<path d="M177.7 112h3M177.7 110.5h3M177.7 101.4h1.8M194.3 104.4h3.1M194.3 105.9h3.1M194.3 101.4h3.1M195.5 109h1.9M195.5 116.6h1.9M195.5 115.1h1.9M195.5 112h1.9M195.5 110.5h1.9M209.6 109h1.5"/>
<path d="M209.6 104.4h1.5M209.6 110.5h1.5M209.6 105.9h1.5M211.1 102.9h12.2v9.1h-12.2zM223.3 109h1.5M223.3 105.9h1.5M86.2 124.2h3.1M86.2 131.8h3.1M86.2 128.8h3.1M86.2 133.4h3.1M86.2 134.9h3.1M86.2 136.4h3.1"/>
<path d="M112.1 131.8h3.1M112.1 128.8h3.1M112.1 121.2h3.1M112.1 122.7h3.1M112.1 125.8h3.1M112.1 127.3h3.1M112.1 130.3h3.1M112.1 133.4h3.1M112.1 134.9h3.1M112.1 136.4h3.1"/>
<circle cx="180.1" cy="78.6" r=".59"/>
<circle cx="88.7" cy="92.2" r=".59"/>
<circle cx="180.1" cy="84.7" r=".59"/>
<circle cx="180.1" cy="81.6" r=".59"/>
<circle cx="194.9" cy="86.2" r=".59"/>
<circle cx="194.9" cy="89.3" r=".59"/>
<circle cx="194.9" cy="93.7" r=".59"/>
<circle cx="194.9" cy="92.2" r=".59"/>
<circle cx="194.9" cy="87.7" r=".59"/>
<circle cx="180.1" cy="104.4" r=".59"/>
<circle cx="180.1" cy="101.4" r=".59"/>
<circle cx="180.1" cy="107.5" r=".59"/>
<circle cx="194.9" cy="115.1" r=".59"/>
<circle cx="194.9" cy="110.5" r=".59"/>
<circle cx="194.9" cy="112" r=".59"/>
<circle cx="194.9" cy="116.6" r=".59"/>
<circle cx="194.9" cy="109" r=".59"/>
</g>
<circle cx="24.6" cy="109.6" r=".6" fill="#830203"/>
<circle cx="24.6" cy="109.6" r=".6" fill="none" stroke="#830203" stroke-width=".13"/>
<path d="M21.5 108.3l.3-.1 .3 .1 .1 .3-.1 .3-.3 .2-.3-.2-.2-.3z" fill-rule="evenodd" fill="#830203"/>
<path d="M21.5 108.3l.3-.1 .3 .1 .1 .3-.1 .3-.3 .2-.3-.2-.1-.3z" fill="none" stroke="#830203" stroke-width=".13"/>
<path d="M21.1 110.1h.7v.6h-.7z" fill="#830203"/>
<g fill="none" stroke="#830203" stroke-width=".13">
<path d="M79.8 77.1h.4M79.8 76.3l-2.6 .8M17 99.8h1.5l-.8 .8zM17.7 98.3v1.5M208 87.7v1.6h.7l-1.2 .5 1.2 .3-1.2 .4 1.2 .4-1.2 .4 1.2 .3-1.2 .5 .5 .1v1.5M208.8 95.3h1.5l-.7 .7zM209.6 93.7v1.6M21.1 110.1h.7v.7h-.7zM29.9 109h1.5M29.9 110.5h1.5M29.9 107.5h1.5M29.9 113.6h1.5"/>
<path d="M29.9 112h1.5M208 110.5v1.5l.7 .2-1.2 .4 1.2 .4-1.2 .4 1.2 .3-1.2 .5 1.2 .3-1.2 .4 .5 .2v1.5M208.8 118.1h1.5l-.7 .8zM209.6 116.6v1.5M64.2 133.4h1.5l-.7 .7zM65 131.8v1.6"/>
</g>
<path d="M77 76.9l.1-.1 .2 .2-.2 .2-.2-.2z" fill-rule="evenodd" fill="#830203"/>
<path d="M77 76.9l.2-.1 .1 .3-.1 .1-.3-.1z" fill="none" stroke="#830203" stroke-width=".13"/>
<path d="M80 76.9l.2-.1 .1 .1v.1l-.1 .2-.3-.2z" fill-rule="evenodd" fill="#830203"/>
<g fill="none" stroke="#830203" stroke-width=".13">
<path d="M113.6 34.4v3M115.2 34.4v3M116.7 34.4v3M118.2 34.4v3M119.7 34.4v3M121.3 34.4v3M122.8 34.4v3M124.3 34.4v3M125.8 34.4v3M127.4 34.4v3M128.9 34.4v3M130.4 34.4v3"/>
<path d="M142.6 26.8h29v6.1h-30.5v-4.6zM142.6 32.9v3M145.6 32.9v3M148.7 32.9v3M151.7 32.9v3M154.8 32.9v3M157.8 32.9v3M160.9 32.9v3M163.9 32.9v3M167 32.9v3M170 32.9v3M177.7 25.3l1.5-1.6h19.7v9.2h-21.2z"/>
<path d="M179.2 32.9v3M182.2 32.9v3M185.3 32.9v3M188.3 32.9v3M191.3 32.9v3M194.3 32.9v3M197.4 32.9v3M34.5 54.2v3.1M63.4 54.2v3.1M71.1 57.3h3M72.6 57.8l.7 .1 .7 .5M72.6 57.8l-.9 .2-.6 .4"/>
<path d="M72.6 55.7v1.6M72.6 57.8v2.5M137.4 55.1l1.2 1.2M138 55.7v1.6M138.6 55.1l-1.2 1.2M140.5 58.2l1.2 1.2M141.1 58.8v1.5M141.7 58.2l-1.2 1.2M141.8 42h1.6l-.8 .8zM142.6 40.5v1.5M181.5 45.4l.7 1.2M182.2 45.1v1.5"/>
<path d="M183 45.4l-.8 1.2M193.6 45.1h1.5l-.8 .7zM194.3 43.5v1.6M21.5 67.9h1.6l-.8 .8zM22.3 66.4v1.5M34.5 60.3v3.1M63.4 60.3v3.1M72.6 78.6v1.5M75.6 77.1h1.6M80 76.9l.2-.1 .2 .3-.2 .1-.3-.1zM80.2 77.1h1.5M90 69.4h1.5l-.7 .8z"/>
<path d="M90.8 67.9v1.5M93.8 67.9h1.6l.2-.6 .4 1.2 .4-1.2 .4 1.2 .3-1.2 .5 1.2 .3-1.2 .4 1.2 .1-.6h1.5M93.8 63.4h1.6l.2-.6 .4 1.1 .4-1.1 .4 1.1 .3-1.1 .5 1.1 .3-1.1 .4 1.1 .1-.5h1.5M101.5 67.9h4.5M101.5 63.4h4.5M102.6 65.9l.8 .8M102.6 66h.1M102.6 65.9l.5 .2M102.6 65.9l.2 .6 .3-.4M102.6 61.3l.8 .9M102.6 61.4h.1M102.6 61.3l.5 .3"/>
<path d="M102.6 61.3l.2 .6 .3-.3M102.6 66.2h.5M102.6 66.1h.5M102.6 66.1h.3M102.6 61.7h.5M102.6 61.6h.5M102.6 61.5h.3M102.7 66.3h.3M102.7 66.4h.2M102.7 61.7h.3M102.7 61.8h.2M103 67.9l1.5-.7v1.5z"/>
<path d="M103 62.6v1.5M103 67.2v1.5M103 63.4l1.5-.8v1.5zM103.2 65.8l.9 .9M103.2 65.8l.5 .3M103.2 65.8l.3 .6 .2-.3M103.2 65.9h.2M103.2 61.3l.9 .8M103.2 61.3l.5 .2M103.2 61.3l.3 .5 .2-.3M103.2 61.3h.2M103.3 66.1h.4"/>
<path d="M103.3 66h.4M103.3 61.6h.4M103.3 61.5h.4M103.3 61.4h.4M103.4 66.3h.2M103.4 66.2h.3M103.4 61.7h.2M103.4 61.7h.3M235.5 77.1v1.5l.6 .1-1.2 .4 1.2 .3-1.2 .5 1.2 .3-1.2 .4 1.2 .4-1.2 .4 .6 .2v1.6M247.7 77.1v1.5l.6 .1-1.2 .4 1.2 .3-1.2 .5 1.2 .3-1.2 .4 1.2 .4-1.2 .4 .6 .2v1.6M259.9 77.1v1.5l.6 .1-1.2 .4 1.2 .3-1.2 .5 1.2 .3-1.2 .4 1.2 .4-1.2 .4 .6 .2v1.6M39.1 98.3l.7 1.2"/>
<path d="M39.1 98.3l-.8 1.2M39.1 98.3v1.5M67.2 98.3h1.6l-.8 .8zM68 84.7v1.5M68 96.8v1.5M68 84.7l.8 1.1M68 84.7l-.8 1.1M71.8 80.1h1.5l-.7 .8zM75.6 92.2h1.6v-.6l.5 1.3 .3-1.3 .4 1.3 .4-1.3 .4 1.3 .3-1.3 .4 1.3 .3-.7h1.5M31.4 101.4h3.1M32.2 100.6l1.5 .8-1.5 .7zM33.7 100.6v1.5"/>
<path d="M36 107.5h1.5l.2-.6 .3 1.2 .5-1.2 .3 1.2 .4-1.2 .4 1.2 .4-1.2 .3 1.2 .3-.6h1.5M43.6 110.5h1.5l.2-.6 .4 1.2 .4-1.2 .3 1.2 .4-1.2 .4 1.2 .4-1.2 .3 1.2 .3-.6h1.5M53.5 115.1h1.6l-.8 .7zM54.3 113.6v1.5M58.9 113.6h2.4M60.8 112.1l.4 .7 .1 .8M61.3 113.6l-.1 .8-.4 .7M61.9 112v3.1M61.9 113.6h1.5M128.9 139.5v1.5l.6 .2-1.2 .3 1.2 .4-1.2 .4 1.2 .4-1.2 .3 1.2 .4-1.2 .4 .6 .2v1.6M183.7 127.3h1.8M183.7 133.4h1.8"/>
<path d="M183.7 130.3h1.8M183.7 134.9h3.1M183.7 136.4h3.1M183.7 137.9h3.1M186.8 125.8h13.6v18.2h-13.6zM200.4 127.3h3.1M200.4 130.3h3.1M200.4 131.8h3.1M201.6 134.9h1.9M201.6 136.4h1.9M201.6 137.9h1.9M211.1 136.4v1.5l.6 .2-1.2 .4 1.2 .4-1.2 .3 1.2 .4-1.2 .4 1.2 .4-1.2 .3 .6 .3v1.5"/>
<path d="M212.6 130.3h1.5M212.6 131.8h1.5M212.6 134.9h1.5M212.6 136.4h1.5M214.1 128.8h12.2v9.1h-12.2zM226.3 131.8h1.6M226.3 134.9h1.6M43.6 156.2h3.1M45.1 156.8l.8 .1 .8 .4M45.1 156.8l-.7 .2-.8 .3M45.1 154.7v1.5M45.1 156.8v2.5"/>
<path d="M49.7 154.7h1.5M55.8 157.8v1.5M60.4 154.7h1.5M63.4 156.2h3.1M65 156.8l.7 .1 .7 .4M65 156.8l-.9 .2-.7 .3M65 154.7v1.5M65 156.8v2.5M89.3 150.1h3M89.3 151.7h3M89.3 148.6h3M89.3 154.7h3"/>
<path d="M89.3 157.8h3M89.3 159.3h3M89.3 156.2h3M89.3 153.2h3M92.3 147.1h18.3v27.4h-18.3zM110.6 154.7h3M110.6 157.8h3M110.6 159.3h3M110.6 156.2h3M128.9 147.1v1.5l.6 .2-1.2 .3 1.2 .4-1.2 .4 1.2 .4-1.2 .3 1.2 .5-1.2 .3 .6 .3v1.5M183.7 141h3.1M183.7 142.5h3.1"/>
<path d="M201.6 141h1.9M201.6 142.5h1.9M211.9 144h1.5l-.8 .8zM212.6 142.5v1.5M73.3 165.4h1.6l-.8 .7zM74.1 163.9v1.5M89.3 162.3h3M89.3 160.8h3M89.3 163.9h3M89.3 165.4h3M89.3 166.9h3M96.9 174.5v3.1"/>
<path d="M98.4 174.5v3.1M99.9 174.5v3.1M101.5 174.5v3.1M103 174.5v3.1M104.5 174.5v3.1M106 174.5v3.1M107.5 174.5v3.1M110.6 162.3h3M110.6 160.8h3M110.6 163.9h3M110.6 165.4h3M110.6 166.9h3"/>
<path d="M118.2 174.5h4.6M119.7 173.8l1.6 .7-1.6 .8zM120.2 175.7l.8 .9M120.6 176.3h.3M120.6 176.2h.3M120.7 176.4h.3M120.7 176.1h.1M120.8 176h.1M120.8 176l-.3 .3 .5 .3M120.8 176l.2 .6M120.8 176.5h.2M120.9 175.6l.9 .9"/>
<path d="M121 176.6h.1M121.2 176.2h.4M121.2 176.2l.6 .3M121.3 173.8v1.5M121.3 176.1h.3M121.3 176.3h.4M121.3 176h.2M121.4 176h.1M121.5 176.4h.2M121.5 176l-.3 .2M121.5 176l.3 .5M125.8 174.5v1.5l.6 .1-1.2 .5 1.2 .3-1.2 .4 1.2 .4-1.2 .4 1.2 .3-1.2 .4 .6 .3v1.5"/>
<path d="M125.1 183.7h1.5l-.8 .7zM125.8 182.1v1.6"/>
<circle cx="186.2" cy="133.4" r=".59"/>
<circle cx="186.2" cy="127.3" r=".59"/>
<circle cx="186.2" cy="130.3" r=".59"/>
<circle cx="201" cy="134.9" r=".59"/>
<circle cx="201" cy="137.9" r=".59"/>
<circle cx="201" cy="136.4" r=".59"/>
<circle cx="201" cy="142.5" r=".59"/>
<circle cx="201" cy="141" r=".59"/>
</g>
<path d="M112.1 31.3h19.8v3.9h-19.8zM51.2 153.2h9.2v4.6h-9.2z" fill="none" stroke="#830203" stroke-width=".17"/>
<path d="M113.6 33.6v.8M115.2 33.6v.8M116.7 33.6v.8M118.2 33.6v.8M119.7 33.6v.8M121.3 33.6v.8M122.8 33.6v.8M124.3 33.6v.8M125.8 33.6v.8M127.4 33.6v.8M128.9 33.6v.8M130.4 33.6v.8" fill="none" stroke="#830203" stroke-width=".34"/>
<path d="M231.6 68.8l.6-.1v1.5a.81 .81 0 0 1-.7-.5 .81 .81 0 0 1 .1-.9z" fill-rule="evenodd" fill="#830203"/>
<path d="M231.7 68.9l.5-.2v1.5a.81 .81 0 0 1-.7-.5 .81 .81 0 0 1 .2-.8z" fill="none" stroke="#830203" stroke-width=".13"/>
<path d="M232.7 68.7a.72 .72 0 0 1 .7 .4 .72 .72 0 0 1-.2 .8l-.4 .3h-.1z" fill-rule="evenodd" fill="#830203"/>
<path d="M229.4 69.4h2M232.7 68.7a.72 .72 0 0 1 .7 .4 .72 .72 0 0 1-.2 .9l-.3 .2h-.2zM233.4 69.4h2.1" fill="none" stroke="#830203" stroke-width=".13"/>
<path d="M243.8 68.8l.5-.1v1.5a.81 .81 0 0 1-.6-.5 .81 .81 0 0 1 .1-.9z" fill-rule="evenodd" fill="#830203"/>
<path d="M243.9 68.9l.5-.2v1.5a.81 .81 0 0 1-.7-.5 .81 .81 0 0 1 .2-.8z" fill="none" stroke="#830203" stroke-width=".13"/>
<path d="M244.9 68.7a.72 .72 0 0 1 .7 .4 .72 .72 0 0 1-.2 .8l-.4 .3h-.1z" fill-rule="evenodd" fill="#830203"/>
<path d="M241.6 69.4h2M244.9 68.7a.72 .72 0 0 1 .7 .4 .72 .72 0 0 1-.2 .9l-.4 .2h-.1zM245.6 69.4h2.1" fill="none" stroke="#830203" stroke-width=".13"/>
<path d="M256 68.8l.5-.1v1.5a.81 .81 0 0 1-.6-.5 .81 .81 0 0 1 .1-.9z" fill-rule="evenodd" fill="#830203"/>
<path d="M256.1 68.9l.5-.2v1.5a.81 .81 0 0 1-.7-.5 .81 .81 0 0 1 .2-.8z" fill="none" stroke="#830203" stroke-width=".13"/>
<path d="M257 68.7a.72 .72 0 0 1 .8 .4 .72 .72 0 0 1-.2 .8l-.4 .3h-.2z" fill-rule="evenodd" fill="#830203"/>
<g fill="none" stroke="#830203" stroke-width=".13">
<path d="M55.8 57.3h3.1M57.3 57.8l.8 .1 .7 .5M57.3 57.8l-.7 .2-.8 .4M57.3 55.7v1.6M57.3 57.8v2.5M78.7 51.2v3M122.2 55.1l1.2 1.2M122.8 55.7v1.6M123.4 55.1l-1.2 1.2M78.7 63.4v3M156.3 60.3v3.1M157.8 60.3v3.1"/>
<path d="M159.4 60.3v3.1M160.9 61.5v1.9M163.3 60.3l.6-1.2 .6 1.2M163.9 60.3v3.1M165.5 61.5v1.9M253.8 69.4h2M257.1 68.7a.72 .72 0 0 1 .7 .4 .72 .72 0 0 1-.2 .9l-.4 .2h-.1zM257.8 69.4h2.1M144.9 95.3h1.5l-.8 .7zM145.6 93.7v1.6M147.2 87.7h2.4M147.2 93.7h2.4"/>
<path d="M149.1 86.2l.4 .7 .1 .8M149.1 92.3l.4 .7 .1 .7M149.6 87.7l-.1 .8-.4 .7M149.6 93.7l-.1 .9-.4 .7M150.2 86.2v3.1M150.2 92.2v3.1M150.2 87.7h1.5M150.2 93.7h1.5M153.3 90.8h1.5M153.7 91.4h2.1M153.7 90.1h2.1M153.9 90.5h1.8v.5h-1.8z"/>
<path d="M154.8 89.3v.8M154.8 91.4v.8M74.4 118.2l.5 .7 .1 .8h-2.4M75 119.7l-.1 .8-.5 .7M75.6 118.1v3.1M75.6 119.7h1.6M81.7 119.7v.9M65.7 123.5h1.5l-.7 .7zM66.5 121.9v1.6M74.4 122.8l.5 .7 .1 .7h-2.4M75 124.2l-.1 .8-.5 .8M75.6 122.7v3.1"/>
<path d="M75.6 124.2h1.6M80.2 121.2h1.5M80.6 121.8h2.1M80.6 120.6h2.1M80.8 120.9h1.8v.5h-1.8zM81.7 121.8v.9M128.1 156.2h1.5l-.7 .8zM128.9 154.7v1.5M93.8 179.1v1.5M139.6 165.4v1.5l.5 .2-1.1 .3 1.1 .4-1.1 .4 1.1 .3-1.1 .4 1.1 .4-1.1 .4 .6 .2v1.6M139.6 173v1.5l.5 .1-1.1 .4 1.1 .4-1.1 .4 1.1 .3-1.1 .5 1.1 .3-1.1 .4 .6 .3v1.5M93.1 180.6h1.5l-.8 .8z"/>
<path d="M138.8 182.1h1.5l-.7 .8zM139.6 180.6v1.5"/>
<circle cx="160.9" cy="60.9" r=".59"/>
<circle cx="165.5" cy="60.9" r=".59"/>
</g>
<path d="M154.8 51.2h12.2v9.1h-12.2z" fill="none" stroke="#830203" stroke-width=".17"/>
<path d="M155.1 163.6l.3 .2-.3 .2-.2-.2z" fill-rule="evenodd" fill="#830203"/>
<path d="M155 163.7l.1-.1 .2 .1 .1 .2-.3 .1-.1-.1z" fill="none" stroke="#830203" stroke-width=".13"/>
<path d="M157.4 163.6l.2 .2-.2 .2-.2-.2z" fill-rule="evenodd" fill="#830203"/>
<path d="M157.3 163.7l.1-.1 .2 .1 .1 .2-.3 .1-.2-.1z" fill="none" stroke="#830203" stroke-width=".13"/>
<path d="M154.8 162.1h.6v.5h-.6z" fill="#830203"/>
<path d="M154.8 162.2h.7v.5h-.7z" fill="none" stroke="#830203" stroke-width=".13"/>
<path d="M157.1 162.1h.6v.5h-.6z" fill="#830203"/>
<path d="M157.1 162.2h.7v.5h-.7z" fill="none" stroke="#830203" stroke-width=".13"/>
<path d="M155.8 162.1h1v.5h-1z" fill="#830203"/>
<g fill="none" stroke="#830203" stroke-width=".13">
<path d="M39.1 90.8h1.5M42.1 93.7v1.6M48.2 93.7v1.6M49.7 90.8h1.5M156.3 159.3v2.3M151 166.9h1.5l-.8 .8zM151.7 165.4v1.5M154.8 161.6h3M155.1 162.6v2.8h2.3v-2.7M155.8 162.2h1v.5h-1zM155.9 165l.8 .4-.8 .3zM156.3 163.3v.6h-3"/>
<path d="M156.3 162.6l.3 .7h-.6zM156.6 164.8l.1 .2v.7l.2 .2M157.4 163.9h2"/>
</g>
<path d="M40.6 89.3h9.1v4.4h-9.1zM156.3 163.2v.1h-.2l.2-.5 .2 .5" fill="none" stroke="#830203" stroke-width=".17"/>
<path d="M177.7 86.2h-10.7v35M197.4 81.6h12.2M197.4 83.2h12.2M167 109h10.7M197.4 104.4h12.2M197.4 105.9h12.2" fill="none" stroke="#008009" stroke-width=".13"/>
<circle cx="167" cy="109" r=".34" fill="#008009"/>
<g fill="none" stroke="#008009" stroke-width=".13">
<path d="M167 71v15.2M115.2 121.2h51.8"/>
<circle cx="167" cy="109" r=".34"/>
</g>
<circle cx="167" cy="86.2" r=".34" fill="#008009"/>
<g fill="none" stroke="#008009" stroke-width=".13">
<path d="M167 121.2v18.3"/>
<circle cx="167" cy="86.2" r=".34"/>
</g>
<circle cx="167" cy="121.2" r=".34" fill="#008009"/>
<g fill="none" stroke="#008009" stroke-width=".13">
<path d="M185.3 35.9v35.1h-18.3M163.9 63.4v3M168.5 87.7v32M168.5 110.5h9.2M183.7 134.9h-4.5v4.6h-12.2"/>
<circle cx="167" cy="121.2" r=".34"/>
</g>
<circle cx="168.5" cy="110.5" r=".34" fill="#008009"/>
<g fill="none" stroke="#008009" stroke-width=".13">
<path d="M168.5 87.7h9.2M115.2 119.7h53.3"/>
<circle cx="168.5" cy="110.5" r=".34"/>
</g>
<circle cx="168.5" cy="87.7" r=".34" fill="#008009"/>
<g fill="none" stroke="#008009" stroke-width=".13">
<path d="M168.5 119.7v16.7"/>
<circle cx="168.5" cy="87.7" r=".34"/>
</g>
<circle cx="168.5" cy="119.6" r=".34" fill="#008009"/>
<g fill="none" stroke="#008009" stroke-width=".13">
<path d="M188.3 35.9v33.5h-32v-6M168.5 69.4v18.3M168.5 136.4h15.2"/>
<circle cx="168.5" cy="119.7" r=".34"/>
</g>
<circle cx="168.5" cy="69.4" r=".34" fill="#008009"/>
<g fill="none" stroke="#008009" stroke-width=".13">
<path d="M177.7 112h-7.7v6.1"/>
<circle cx="168.5" cy="69.4" r=".34"/>
</g>
<circle cx="170" cy="112" r=".34" fill="#008009"/>
<g fill="none" stroke="#008009" stroke-width=".13">
<path d="M170 67.9v44.1M170 89.3h7.7M115.2 118.1h54.8"/>
<circle cx="170" cy="112" r=".34"/>
</g>
<circle cx="170" cy="89.2" r=".34" fill="#008009"/>
<g fill="none" stroke="#008009" stroke-width=".13">
<path d="M170 118.1v19.8"/>
<circle cx="170" cy="89.3" r=".34"/>
</g>
<circle cx="170" cy="118.1" r=".34" fill="#008009"/>
<g fill="none" stroke="#008009" stroke-width=".13">
<path d="M179.2 35.9v32h-21.4v-4.5M170 137.9h13.7"/>
<circle cx="170" cy="118.1" r=".34"/>
</g>
<circle cx="170" cy="67.9" r=".34" fill="#008009"/>
<g fill="none" stroke="#008009" stroke-width=".13">
<path d="M177.7 81.6h-15.3v82.3h-3M209.6 87.7h-6.1v6h-6.1M42.1 107.5h29l3 3h12.1M209.6 110.5h-6.1v6.1h-6.1M115.2 136.4h47.2"/>
<circle cx="170" cy="67.9" r=".34"/>
</g>
<circle cx="162.4" cy="136.4" r=".34" fill="#008009"/>
<g fill="none" stroke="#008009" stroke-width=".13">
<path d="M125.8 37.4v62.4h-10.6M128.9 37.4v56.3h-13.7M130.4 37.4v54.8h-15.2M197.4 35.9v7.6M119.7 57.3v65.4h-4.5M99.9 67.9h1.6M106 63.4h12.2v45.6h-3M177.7 78.6h-12.2v51.7h-50.3M81.7 92.2h4.5M177.7 84.7h-4.6v15.1h-36.6l-1.5 1.6v13.7h-19.8M31.4 110.5h12.2M36 107.5l-4.6 1.5"/>
<path d="M63.4 113.6h22.8M115.2 112h35v12.2h32v3.1h1.5M115.2 107.5h38.1v21.3h25.9v4.6h4.5M115.2 116.6h18.3v22.9l6.1 6.1v19.8M177.7 101.4h-13.8v25.9h-48.7M177.7 104.4h-3.1v30.5h-59.4M177.7 107.5h-1.6v6.1h-60.9"/>
<circle cx="162.4" cy="136.4" r=".34"/>
</g>
<circle cx="81.7" cy="92.2" r=".34" fill="#008009"/>
<g fill="none" stroke="#008009" stroke-width=".13">
<path d="M191.3 35.9v7.6M194.3 35.9v7.6M75.6 77.1h-3v1.5M81.7 77.1v15.1M31.4 96.8h-13.7v1.5"/>
<circle cx="81.7" cy="92.2" r=".34"/>
</g>
<circle cx="31.4" cy="96.8" r=".34" fill="#008009"/>
<g fill="none" stroke="#008009" stroke-width=".13">
<path d="M17.7 80.1v16.7M31.4 96.8h25.9"/>
<circle cx="31.4" cy="96.8" r=".34"/>
</g>
<circle cx="17.7" cy="96.8" r=".34" fill="#008009"/>
<g fill="none" stroke="#008009" stroke-width=".13">
<path d="M57.3 96.8h10.7"/>
<circle cx="17.7" cy="96.8" r=".34"/>
</g>
<circle cx="57.3" cy="96.8" r=".34" fill="#008009"/>
<g fill="none" stroke="#008009" stroke-width=".13">
<path d="M90.8 67.9h3M42.1 95.3v1.5"/>
<circle cx="57.3" cy="96.8" r=".34"/>
</g>
<circle cx="90.8" cy="67.9" r=".34" fill="#008009"/>
<g fill="none" stroke="#008009" stroke-width=".13">
<path d="M93.8 63.4l-3 4.5"/>
<circle cx="90.8" cy="67.9" r=".34"/>
</g>
<circle cx="26.8" cy="63.3" r=".34" fill="#008009"/>
<g fill="none" stroke="#008009" stroke-width=".13">
<path d="M22.3 63.4h4.6"/>
<circle cx="26.9" cy="63.4" r=".34"/>
</g>
<circle cx="22.3" cy="63.3" r=".34" fill="#008009"/>
<g fill="none" stroke="#008009" stroke-width=".13">
<path d="M22.3 63.4v3M46.7 63.4h7.6"/>
<circle cx="22.3" cy="63.4" r=".34"/>
</g>
<circle cx="54.3" cy="63.3" r=".34" fill="#008009"/>
<g fill="none" stroke="#008009" stroke-width=".13">
<path d="M26.9 63.4h7.6M72.6 60.3v3.1h-18.3"/>
<circle cx="54.3" cy="63.4" r=".34"/>
</g>
<circle cx="46.7" cy="63.3" r=".34" fill="#008009"/>
<g fill="none" stroke="#008009" stroke-width=".13">
<path d="M34.5 63.4h12.2"/>
<circle cx="46.7" cy="63.4" r=".34"/>
</g>
<circle cx="34.5" cy="63.3" r=".34" fill="#008009"/>
<circle cx="34.5" cy="63.4" r=".34" fill="none" stroke="#008009" stroke-width=".13"/>
<circle cx="63.4" cy="63.3" r=".34" fill="#008009"/>
<g fill="none" stroke="#008009" stroke-width=".13">
<path d="M57.3 60.3v3.1M72.6 63.4v3h6.1M65 131.8h21.2M81.7 131.8v1.6"/>
<circle cx="63.4" cy="63.4" r=".34"/>
</g>
<circle cx="81.7" cy="131.8" r=".34" fill="#008009"/>
<g fill="none" stroke="#008009" stroke-width=".13">
<path d="M86.2 133.4h-4.5v1.5"/>
<circle cx="81.7" cy="131.8" r=".34"/>
</g>
<circle cx="81.7" cy="133.4" r=".34" fill="#008009"/>
<g fill="none" stroke="#008009" stroke-width=".13">
<path d="M86.2 134.9h-4.5v1.5"/>
<circle cx="81.7" cy="133.4" r=".34"/>
</g>
<circle cx="81.7" cy="134.9" r=".34" fill="#008009"/>
<g fill="none" stroke="#008009" stroke-width=".13">
<path d="M31.4 113.6l15.3 15.2h39.5M81.7 136.4h4.5M81.7 128.8v3"/>
<circle cx="81.7" cy="134.9" r=".34"/>
</g>
<circle cx="81.7" cy="128.8" r=".34" fill="#008009"/>
<g fill="none" stroke="#008009" stroke-width=".13">
<path d="M208 93.7h1.6M54.3 113.6h4.6M208 116.6h1.6M55.8 159.3l3.1 3h30.4M89.3 148.6h-12.1l-3.1 3.1v10.6M211.1 142.5h1.5"/>
<circle cx="81.7" cy="128.8" r=".34"/>
</g>
<circle cx="74.1" cy="162.3" r=".34" fill="#008009"/>
<g fill="none" stroke="#008009" stroke-width=".13">
<path d="M45.1 159.3l3.1 3h10.7M74.1 162.3v1.6"/>
<circle cx="74.1" cy="162.3" r=".34"/>
</g>
<circle cx="58.8" cy="162.3" r=".34" fill="#008009"/>
<g fill="none" stroke="#008009" stroke-width=".13">
<path d="M65 159.3l3 3"/>
<circle cx="58.9" cy="162.3" r=".34"/>
</g>
<circle cx="68" cy="162.3" r=".34" fill="#008009"/>
<g fill="none" stroke="#008009" stroke-width=".13">
<path d="M113.6 37.4v10.7M142.6 35.9v4.6M147.2 87.7v6h-1.6M147.2 90.8h6.1M72.6 119.7v4.5M80.2 121.2l-1.5 .7h-12.2M113.6 154.7h4.6M96.9 177.6l-3.1 1.5M107.5 177.6v3M162.4 179.1h-22.8v1.5M125.8 180.6v1.5"/>
<circle cx="68" cy="162.3" r=".34"/>
</g>
<circle cx="139.5" cy="179.1" r=".34" fill="#008009"/>
<g fill="none" stroke="#008009" stroke-width=".13">
<path d="M86.2 95.3h-4.5v7.6M86.2 102.9h-54.8v4.6M128.9 153.2v1.5M153.3 163.9h-1.6v1.5"/>
<circle cx="139.6" cy="179.1" r=".34"/>
</g>
<circle cx="81.7" cy="102.9" r=".34" fill="#008009"/>
<g fill="none" stroke="#008009" stroke-width=".13">
<path d="M31.4 101.4v1.5"/>
<circle cx="81.7" cy="102.9" r=".34"/>
</g>
<circle cx="31.4" cy="102.9" r=".34" fill="#008009"/>
<g fill="none" stroke="#008009" stroke-width=".13">
<path d="M182.2 35.9v9.2M68 86.2v6h7.6M86.2 99.8h-10.6v1.6h10.6"/>
<circle cx="31.4" cy="102.9" r=".34"/>
</g>
<circle cx="75.6" cy="101.3" r=".34" fill="#008009"/>
<g fill="none" stroke="#008009" stroke-width=".13">
<path d="M75.6 101.4v3h10.6"/>
<circle cx="75.6" cy="101.4" r=".34"/>
</g>
<circle cx="75.6" cy="104.4" r=".34" fill="#008009"/>
<g fill="none" stroke="#008009" stroke-width=".13">
<path d="M74.1 92.2v7.6h1.5M75.6 104.4v1.5h10.6"/>
<circle cx="75.6" cy="104.4" r=".34"/>
</g>
<circle cx="75.6" cy="99.8" r=".34" fill="#008009"/>
<circle cx="75.6" cy="99.8" r=".34" fill="none" stroke="#008009" stroke-width=".13"/>
<circle cx="74.1" cy="92.2" r=".34" fill="#008009"/>
<g fill="none" stroke="#008009" stroke-width=".13">
<path d="M57.3 92.2h10.7"/>
<circle cx="74.1" cy="92.2" r=".34"/>
</g>
<circle cx="57.3" cy="92.2" r=".34" fill="#008009"/>
<circle cx="57.3" cy="92.2" r=".34" fill="none" stroke="#008009" stroke-width=".13"/>
<circle cx="68" cy="92.2" r=".34" fill="#008009"/>
<g fill="none" stroke="#008009" stroke-width=".13">
<path d="M39.1 99.8v1.6h-4.6M51.2 90.8h6.1v1.4M42.1 154.7h7.6"/>
<circle cx="68" cy="92.2" r=".34"/>
</g>
<circle cx="45.1" cy="154.7" r=".34" fill="#008009"/>
<g fill="none" stroke="#008009" stroke-width=".13">
<path d="M42.1 150.1v4.6"/>
<circle cx="45.1" cy="154.7" r=".34"/>
</g>
<circle cx="26.8" cy="54.2" r=".34" fill="#008009"/>
<g fill="none" stroke="#008009" stroke-width=".13">
<path d="M22.3 54.2h4.6"/>
<circle cx="26.9" cy="54.2" r=".34"/>
</g>
<circle cx="54.3" cy="54.2" r=".34" fill="#008009"/>
<g fill="none" stroke="#008009" stroke-width=".13">
<path d="M26.9 54.2h7.6M46.7 54.2h25.9v1.5"/>
<circle cx="54.3" cy="54.2" r=".34"/>
</g>
<circle cx="46.7" cy="54.2" r=".34" fill="#008009"/>
<g fill="none" stroke="#008009" stroke-width=".13">
<path d="M34.5 54.2h12.2"/>
<circle cx="46.7" cy="54.2" r=".34"/>
</g>
<circle cx="34.5" cy="54.2" r=".34" fill="#008009"/>
<circle cx="34.5" cy="54.2" r=".34" fill="none" stroke="#008009" stroke-width=".13"/>
<circle cx="63.4" cy="54.2" r=".34" fill="#008009"/>
<g fill="none" stroke="#008009" stroke-width=".13">
<path d="M116.7 37.4v10.7M57.3 54.2v1.5M78.7 51.2h-6.1v3M229.4 58.8v27.4h-4.6"/>
<circle cx="63.4" cy="54.2" r=".34"/>
</g>
<circle cx="229.4" cy="69.4" r=".34" fill="#008009"/>
<g fill="none" stroke="#008009" stroke-width=".13">
<path d="M118.2 37.4v10.7M238.5 58.8v24.4h-13.7"/>
<circle cx="229.4" cy="69.4" r=".34"/>
</g>
<circle cx="235.5" cy="83.1" r=".34" fill="#008009"/>
<g fill="none" stroke="#008009" stroke-width=".13">
<path d="M119.7 37.4v10.7M241.6 58.8v50.2h-16.8"/>
<circle cx="235.5" cy="83.2" r=".34"/>
</g>
<circle cx="241.6" cy="69.4" r=".34" fill="#008009"/>
<g fill="none" stroke="#008009" stroke-width=".13">
<path d="M121.3 37.4v10.7M250.7 58.8v47.1h-25.9M247.7 83.2h3"/>
<circle cx="241.6" cy="69.4" r=".34"/>
</g>
<circle cx="250.7" cy="83.1" r=".34" fill="#008009"/>
<g fill="none" stroke="#008009" stroke-width=".13">
<path d="M122.8 37.4v10.7M253.8 58.8v76.1h-25.9M99.9 63.4h1.6M203.5 130.3h9.1M203.5 131.8h9.1M212.6 136.4h-6.1v6.1h-3"/>
<circle cx="250.7" cy="83.2" r=".34"/>
</g>
<circle cx="253.7" cy="69.4" r=".34" fill="#008009"/>
<g fill="none" stroke="#008009" stroke-width=".13">
<path d="M124.3 37.4v10.7M262.9 58.8v73h-35M259.9 83.2h3"/>
<circle cx="253.8" cy="69.4" r=".34"/>
</g>
<circle cx="262.9" cy="83.1" r=".34" fill="#008009"/>
<g fill="none" stroke="#008009" stroke-width=".13">
<path d="M115.2 37.4v10.7M127.4 37.4v60.9h-12.2M22.3 78.6v12.2h16.8M31.4 90.8v1.4M86.2 109h-12.1l-1.5 1.5h-22.9M65 150.1h24.3M87.7 150.1l1.6 1.6"/>
<circle cx="262.9" cy="83.2" r=".34"/>
</g>
<circle cx="87.7" cy="150.1" r=".34" fill="#008009"/>
<g fill="none" stroke="#008009" stroke-width=".13">
<path d="M65 150.1v4.6h-3.1"/>
<circle cx="87.7" cy="150.1" r=".34"/>
</g>
<circle cx="64.9" cy="154.7" r=".34" fill="#008009"/>
<g fill="none" stroke="#008009" stroke-width=".13">
<path d="M145.6 35.9v12.2M167 35.9v9.2h-21.4M106 177.6v4.5"/>
<circle cx="65" cy="154.7" r=".34"/>
</g>
<circle cx="145.6" cy="45" r=".34" fill="#008009"/>
<g fill="none" stroke="#008009" stroke-width=".13">
<path d="M115.2 104.4h27.4l4.6 4.6v22.8h35l1.5-1.5M115.2 131.8h7.6l6.1 6.1v1.6M115.2 133.4h3v6.1l-3 3h-29l-3 3.1v10.6l3 3.1h3.1M128.9 145.6v1.5h-4.6v-3.1h-36.6l-2.9 3.1v7.6l2.9 3.1h1.6"/>
<circle cx="145.6" cy="45.1" r=".34"/>
</g>
<circle cx="128.9" cy="147.1" r=".34" fill="#008009"/>
<g fill="none" stroke="#008009" stroke-width=".13">
<path d="M148.7 35.9v6.1M151.7 35.9v6.1M154.8 35.9v6.1M157.8 35.9v6.1M160.9 35.9v6.1M163.9 35.9v6.1M170 35.9v6.1M122.8 57.3v68.5h-7.6M138 57.3v39.5h-22.8M106 67.9h18.3v35h-9.1M141.1 60.3v35h-25.9M165.5 63.4v7.6h-42.7"/>
<path d="M235.5 69.4v7.7M247.7 69.4v7.7M259.9 69.4v7.7M151.7 87.7h7.7v4.5h18.3M154.8 87.7v1.6M115.2 128.8h6.1v41.1h-32v-3M89.3 153.2h-3.1v16.7M89.3 154.7h-1.6v16.8M113.6 157.8h4.6v16.7M113.6 156.2h4.6M98.4 177.6v10.6M99.9 177.6v10.6"/>
<path d="M113.6 165.4h1.6M113.6 163.9h1.6M113.6 162.3h1.6M113.6 160.8h1.6M122.8 174.5h3"/>
<circle cx="128.9" cy="147.1" r=".34"/>
</g>
<circle cx="122.8" cy="71" r=".34" fill="#008009"/>
<g fill="none" stroke="#008009" stroke-width=".13">
<path d="M151.7 93.7h26M154.8 92.2v1.5M159.4 96.8v44.2h24.3M159.4 115.1h18.3"/>
<circle cx="122.8" cy="71" r=".34"/>
</g>
<circle cx="159.3" cy="115.1" r=".34" fill="#008009"/>
<g fill="none" stroke="#008009" stroke-width=".13">
<path d="M197.4 78.6h1.5v18.2h-39.5M77.2 119.7h9M77.2 124.2h9M81.7 122.7v1.5M139.6 171.5v1.5h-4.6v15.2h-32v-10.6"/>
<circle cx="159.4" cy="115.1" r=".34"/>
</g>
<circle cx="139.5" cy="173" r=".34" fill="#008009"/>
<g fill="none" stroke="#008009" stroke-width=".13">
<path d="M113.6 159.3h42.7"/>
<circle cx="139.6" cy="173" r=".34"/>
</g>
<use href="#words"/>
</svg>
